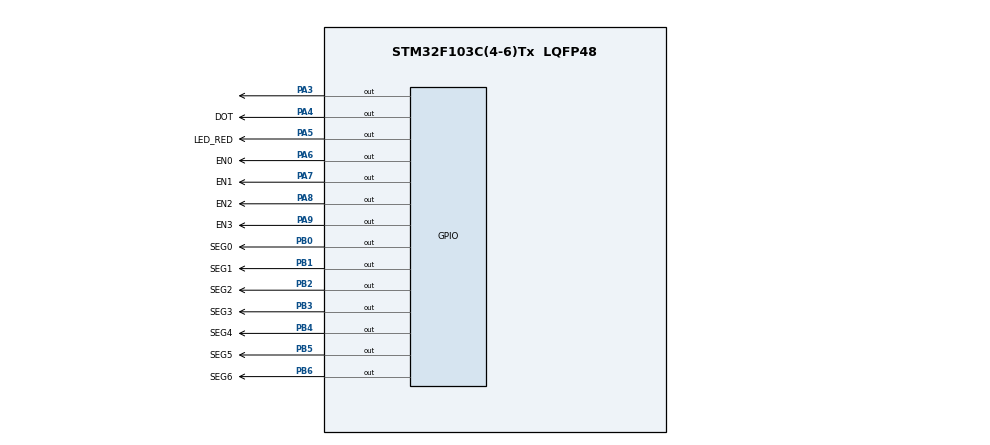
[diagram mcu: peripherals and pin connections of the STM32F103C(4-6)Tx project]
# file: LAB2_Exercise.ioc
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Mcu.Family=STM32F1
Mcu.Name=STM32F103C(4-6)Tx
Mcu.Package=LQFP48
NVIC.PriorityGroup=NVIC_PRIORITYGROUP_4
NVIC.TIM2_IRQn=true\:0\:0\:false\:false\:true\:true\:true
PA3.Signal=GPIO_Output
PA4.GPIO_Label=DOT
PA4.Signal=GPIO_Output
PA5.GPIO_Label=LED_RED
PA5.Signal=GPIO_Output
PA6.GPIO_Label=EN0
PA6.Signal=GPIO_Output
PA7.GPIO_Label=EN1
PA7.Signal=GPIO_Output
PA8.GPIO_Label=EN2
PA8.Signal=GPIO_Output
PA9.GPIO_Label=EN3
PA9.Signal=GPIO_Output
PB0.GPIO_Label=SEG0
PB0.Signal=GPIO_Output
PB1.GPIO_Label=SEG1
PB1.Signal=GPIO_Output
PB2.GPIO_Label=SEG2
PB2.Signal=GPIO_Output
PB3.GPIO_Label=SEG3
PB3.Signal=GPIO_Output
PB4.GPIO_Label=SEG4
PB4.Signal=GPIO_Output
PB5.GPIO_Label=SEG5
PB5.Signal=GPIO_Output
PB6.GPIO_Label=SEG6
PB6.Signal=GPIO_Output
ProjectManager.HeapSize=0x200
ProjectManager.StackSize=0x400
ProjectManager.TargetToolchain=STM32CubeIDE
RCC.APB1Freq_Value=8000000
RCC.APB2Freq_Value=8000000
TIM2.Period=9
TIM2.Prescaler=7999
VP_SYS_VS_ND.Mode=No_Debug
VP_TIM2_VS_ClockSourceINT.Mode=Internal
board=custom

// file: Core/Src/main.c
/* USER CODE BEGIN Header */
/**
  ******************************************************************************
  * @file           : main.c
  * @brief          : Main program body
  ******************************************************************************
  * @attention
  *
  * <h2><center>&copy; Copyright (c) 2023 STMicroelectronics.
  * All rights reserved.</center></h2>
  *
  * This software component is licensed by ST under BSD 3-Clause license,
  * the "License"; You may not use this file except in compliance with the
  * License. You may obtain a copy of the License at:
  *                        opensource.org/licenses/BSD-3-Clause
  *
  ******************************************************************************
  */
/* USER CODE END Header */
#include "main.h"

TIM_HandleTypeDef htim2;

/* USER CODE BEGIN PV */
int digit1 = 1;
int digit2 = 0;
int digit3 = 2;
int digit4 = 0;
int led_buffer[4] ;

void SystemClock_Config(void);
static void MX_GPIO_Init(void);
static void MX_TIM2_Init(void);
int timer1_flag = 0;
int counter1 = 0;
int timer2_flag = 0;
int counter2 = 0;
int timer3_flag = 0;
int counter3 = 0;
int timer0_flag = 0;
int counter0 =0;
int counter5 = 0;
int timer5_flag = 0;

void setTimer1(int duration){
	counter1 = duration;
	timer1_flag = 0;
}
void setTimer2(int duration){
	counter2 = duration;
	timer2_flag = 0;
}
void setTimer3(int duration){
	counter3 = duration;
	timer3_flag = 0;
}
void setTimer0(int duration){
	counter0 = duration;
	timer0_flag = 0;
}
void setTimer5( int duration ){
	counter5 = duration;
	timer5_flag = 0;
}
void timerRun(){
	if(counter1 > 0){
		counter1--;
		if(counter1 <= 0){
			timer1_flag = 1;
              }
	}
	 if(counter2 > 0){
			counter2 -- ;
				if(counter2 <= 0){
					timer2_flag = 1;
				}
			}
		if(counter3 > 0){
				counter3--;
				if(counter3 <= 0){
					timer3_flag = 1;
				}
			}
		if(counter0 > 0){
			counter0--;
			if (counter0 <= 0){
				timer0_flag = 1 ;
			}
		}
		if(counter5 > 0){
			counter5--;
			if (counter5 <= 0){
				timer5_flag = 1;
			}
		}
}

void HAL_TIM_PeriodElapsedCallback (TIM_HandleTypeDef *htim2 )
{
     timerRun();

}

void updateClockBuffer(int a, int b){
	digit1 = a/10;
	digit2 = a%10;
	digit3 = b/10;
	digit4 = b%10;
	led_buffer[0] = digit1;
	led_buffer[1] = digit2;
	led_buffer[2] = digit3;
	led_buffer[3] = digit4;
}

void SCAN(int n){
	switch (led_buffer[n]){
	   case 0:
	  		HAL_GPIO_WritePin(SEG0_GPIO_Port, SEG0_Pin, 0 );
	  		HAL_GPIO_WritePin(SEG1_GPIO_Port, SEG1_Pin, 0);
	  		HAL_GPIO_WritePin(SEG2_GPIO_Port, SEG2_Pin, 0);
	  		HAL_GPIO_WritePin(SEG3_GPIO_Port, SEG3_Pin,0 );
	  		HAL_GPIO_WritePin(SEG4_GPIO_Port, SEG4_Pin,0 );
	  		HAL_GPIO_WritePin(SEG5_GPIO_Port, SEG5_Pin, 0);
	  		HAL_GPIO_WritePin(SEG6_GPIO_Port, SEG6_Pin, 1);
	  		break;

	   case 1:
	 		HAL_GPIO_WritePin(SEG0_GPIO_Port, SEG0_Pin, 1);
	 		HAL_GPIO_WritePin(SEG1_GPIO_Port, SEG1_Pin, 0);
	 		HAL_GPIO_WritePin(SEG2_GPIO_Port, SEG2_Pin, 0);
	 		HAL_GPIO_WritePin(SEG3_GPIO_Port, SEG3_Pin, 1);
	 		HAL_GPIO_WritePin(SEG4_GPIO_Port, SEG4_Pin, 1);
	 		HAL_GPIO_WritePin(SEG5_GPIO_Port, SEG5_Pin, 1);
	 		HAL_GPIO_WritePin(SEG6_GPIO_Port, SEG6_Pin, 1);
	 		break;
	   case 2:
	 		HAL_GPIO_WritePin(SEG0_GPIO_Port, SEG0_Pin, 0);
	 		HAL_GPIO_WritePin(SEG1_GPIO_Port, SEG1_Pin, 0);
	 		HAL_GPIO_WritePin(SEG2_GPIO_Port, SEG2_Pin, 1);
	 		HAL_GPIO_WritePin(SEG3_GPIO_Port, SEG3_Pin, 0);
	 		HAL_GPIO_WritePin(SEG4_GPIO_Port, SEG4_Pin, 0);
	 		HAL_GPIO_WritePin(SEG5_GPIO_Port, SEG5_Pin, 1);
	 		HAL_GPIO_WritePin(SEG6_GPIO_Port, SEG6_Pin, 0);
	 		break;
	   case 3:
			HAL_GPIO_WritePin(SEG0_GPIO_Port, SEG0_Pin, 0);
			HAL_GPIO_WritePin(SEG1_GPIO_Port, SEG1_Pin, 0);
			HAL_GPIO_WritePin(SEG2_GPIO_Port, SEG2_Pin, 0);
			HAL_GPIO_WritePin(SEG3_GPIO_Port, SEG3_Pin, 0);
			HAL_GPIO_WritePin(SEG4_GPIO_Port, SEG4_Pin, 1);
			HAL_GPIO_WritePin(SEG5_GPIO_Port, SEG5_Pin, 1);
			HAL_GPIO_WritePin(SEG6_GPIO_Port, SEG6_Pin, 0);
			break;
	   case 4:
			HAL_GPIO_WritePin(SEG0_GPIO_Port, SEG0_Pin, 1 );
			HAL_GPIO_WritePin(SEG1_GPIO_Port, SEG1_Pin, 0 );
			HAL_GPIO_WritePin(SEG2_GPIO_Port, SEG2_Pin, 0);
			HAL_GPIO_WritePin(SEG3_GPIO_Port, SEG3_Pin, 1 );
			HAL_GPIO_WritePin(SEG4_GPIO_Port, SEG4_Pin, 1);
			HAL_GPIO_WritePin(SEG5_GPIO_Port, SEG5_Pin, 0);
			HAL_GPIO_WritePin(SEG6_GPIO_Port, SEG6_Pin, 0);
			break;
	   case 5:
			HAL_GPIO_WritePin(SEG0_GPIO_Port, SEG0_Pin, 0 );
			HAL_GPIO_WritePin(SEG1_GPIO_Port, SEG1_Pin, 1 );
			HAL_GPIO_WritePin(SEG2_GPIO_Port, SEG2_Pin, 0);
			HAL_GPIO_WritePin(SEG3_GPIO_Port, SEG3_Pin, 0 );
			HAL_GPIO_WritePin(SEG4_GPIO_Port, SEG4_Pin, 1 );
			HAL_GPIO_WritePin(SEG5_GPIO_Port, SEG5_Pin, 0);
			HAL_GPIO_WritePin(SEG6_GPIO_Port, SEG6_Pin, 0);
			break;
	   case 6:

			HAL_GPIO_WritePin(SEG0_GPIO_Port, SEG0_Pin, 0 );
			HAL_GPIO_WritePin(SEG1_GPIO_Port, SEG1_Pin, 1 );
			HAL_GPIO_WritePin(SEG2_GPIO_Port, SEG2_Pin, 0);
			HAL_GPIO_WritePin(SEG3_GPIO_Port, SEG3_Pin,0 );
			HAL_GPIO_WritePin(SEG4_GPIO_Port, SEG4_Pin,0 );
			HAL_GPIO_WritePin(SEG5_GPIO_Port, SEG5_Pin, 0);
			HAL_GPIO_WritePin(SEG6_GPIO_Port, SEG6_Pin, 0);
			break;
	   case 7:
			HAL_GPIO_WritePin(SEG0_GPIO_Port, SEG0_Pin, 0 );
			HAL_GPIO_WritePin(SEG1_GPIO_Port, SEG1_Pin, 0 );
			HAL_GPIO_WritePin(SEG2_GPIO_Port, SEG2_Pin, 0);
			HAL_GPIO_WritePin(SEG3_GPIO_Port, SEG3_Pin, 1 );
			HAL_GPIO_WritePin(SEG4_GPIO_Port, SEG4_Pin, 1 );
			HAL_GPIO_WritePin(SEG5_GPIO_Port, SEG5_Pin, 1);
			HAL_GPIO_WritePin(SEG6_GPIO_Port, SEG6_Pin, 1);
			break;
	   case 8:
			HAL_GPIO_WritePin(SEG0_GPIO_Port, SEG0_Pin, 0 );
			HAL_GPIO_WritePin(SEG1_GPIO_Port, SEG1_Pin, 0 );
			HAL_GPIO_WritePin(SEG2_GPIO_Port, SEG2_Pin, 0);
			HAL_GPIO_WritePin(SEG3_GPIO_Port, SEG3_Pin,0 );
			HAL_GPIO_WritePin(SEG4_GPIO_Port, SEG4_Pin,0 );
			HAL_GPIO_WritePin(SEG5_GPIO_Port, SEG5_Pin, 0);
			HAL_GPIO_WritePin(SEG6_GPIO_Port, SEG6_Pin, 0);
			break;
	   case 9:
			HAL_GPIO_WritePin(SEG0_GPIO_Port, SEG0_Pin, 0 );
			HAL_GPIO_WritePin(SEG1_GPIO_Port, SEG1_Pin, 0 );
			HAL_GPIO_WritePin(SEG2_GPIO_Port, SEG2_Pin, 0);
			HAL_GPIO_WritePin(SEG3_GPIO_Port, SEG3_Pin,0 );
			HAL_GPIO_WritePin(SEG4_GPIO_Port, SEG4_Pin, 1);
			HAL_GPIO_WritePin(SEG5_GPIO_Port, SEG5_Pin, 0);
			HAL_GPIO_WritePin(SEG6_GPIO_Port, SEG6_Pin, 0);
			break;
	   default:
		   break;
	}
}

void update7SEG(int index_led){
	switch (index_led){
	case 0:
		   HAL_GPIO_WritePin(EN0_GPIO_Port, EN0_Pin, 0);
		   HAL_GPIO_WritePin(EN1_GPIO_Port, EN1_Pin, 1);
		   HAL_GPIO_WritePin(EN2_GPIO_Port, EN2_Pin, 1);
		   HAL_GPIO_WritePin(EN3_GPIO_Port, EN3_Pin, 1);
		   SCAN(index_led);
		   break;
	case 1:
		   HAL_GPIO_WritePin(EN0_GPIO_Port, EN0_Pin, 1);
		   HAL_GPIO_WritePin(EN1_GPIO_Port, EN1_Pin, 0);
		   HAL_GPIO_WritePin(EN2_GPIO_Port, EN2_Pin, 1);
		   HAL_GPIO_WritePin(EN3_GPIO_Port, EN3_Pin, 1);
		   SCAN(index_led);
		   break;
	case 2:
		   HAL_GPIO_WritePin(EN0_GPIO_Port, EN0_Pin, 1);
		   HAL_GPIO_WritePin(EN1_GPIO_Port, EN1_Pin, 1);
		   HAL_GPIO_WritePin(EN2_GPIO_Port, EN2_Pin, 0);
		   HAL_GPIO_WritePin(EN3_GPIO_Port, EN3_Pin, 1);
		   SCAN(index_led);
		   break;
	case 3:
		   HAL_GPIO_WritePin(EN0_GPIO_Port, EN0_Pin, 1);
		   HAL_GPIO_WritePin(EN1_GPIO_Port, EN1_Pin, 1);
		   HAL_GPIO_WritePin(EN2_GPIO_Port, EN2_Pin, 1);
		   HAL_GPIO_WritePin(EN3_GPIO_Port, EN3_Pin, 0 );
		   SCAN(index_led);
		   break;
	default:
		break;
	}
}
const int MAX_LED_MATRIX = 8;
int index_led_matrix = 0;
uint8_t matrix_buffer [8] = {
  0b11100111,
  0b11000011,
  0b10011001,
  0b10011001,
  0b10000001,
  0b10000001,
  0b10011001,
  0b10011001,
};

void SCAN_LED_MATRIX(int index){

	  HAL_GPIO_WritePin(ROW0_GPIO_Port, ROW0_Pin, 0);
	  HAL_GPIO_WritePin(ROW1_GPIO_Port, ROW1_Pin, 0);
	  HAL_GPIO_WritePin(ROW2_GPIO_Port, ROW2_Pin, 0);
	  HAL_GPIO_WritePin(ROW3_GPIO_Port, ROW3_Pin, 0);
	  HAL_GPIO_WritePin(ROW4_GPIO_Port, ROW4_Pin, 0);
	  HAL_GPIO_WritePin(ROW5_GPIO_Port, ROW5_Pin, 0);
	  HAL_GPIO_WritePin(ROW6_GPIO_Port, ROW6_Pin, 0);
	  HAL_GPIO_WritePin(ROW7_GPIO_Port, ROW7_Pin, 0);

	  uint8_t row_value = matrix_buffer[index] >> 1;
	  if(row_value & 0b00000001) HAL_GPIO_WritePin(ROW0_GPIO_Port, ROW0_Pin, 1);
	  if(row_value & 0b00000010) HAL_GPIO_WritePin(ROW1_GPIO_Port, ROW1_Pin, 1);
	  if(row_value & 0b00000100) HAL_GPIO_WritePin(ROW2_GPIO_Port, ROW2_Pin, 1);
	  if(row_value & 0b00001000) HAL_GPIO_WritePin(ROW3_GPIO_Port, ROW3_Pin, 1);
	  if(row_value & 0b00010000) HAL_GPIO_WritePin(ROW4_GPIO_Port, ROW4_Pin, 1);
	  if(row_value & 0b00100000) HAL_GPIO_WritePin(ROW5_GPIO_Port, ROW5_Pin, 1);
	  if(row_value & 0b01000000) HAL_GPIO_WritePin(ROW6_GPIO_Port, ROW6_Pin, 1);
	  if(row_value & 0b10000000) HAL_GPIO_WritePin(ROW7_GPIO_Port, ROW7_Pin, 1);
}
uint8_t matrix_buffer_col [8] = {
		 0b00000001
		,0b00000010
		,0b00000100
		,0b00001000
		,0b00010000
		,0b00100000
		,0b01000000
		,0b10000000
};
void SCAN_LED_MATRIX_COL(int index){
	  HAL_GPIO_WritePin(ENM0_GPIO_Port, ENM0_Pin, 1);
	  HAL_GPIO_WritePin(ENM1_GPIO_Port, ENM1_Pin, 1);
	  HAL_GPIO_WritePin(ENM2_GPIO_Port, ENM2_Pin, 1);
	  HAL_GPIO_WritePin(ENM3_GPIO_Port, ENM3_Pin, 1);
	  HAL_GPIO_WritePin(ENM4_GPIO_Port, ENM4_Pin, 1);
	  HAL_GPIO_WritePin(ENM5_GPIO_Port, ENM5_Pin, 1);
	  HAL_GPIO_WritePin(ENM6_GPIO_Port, ENM6_Pin, 1);
	  HAL_GPIO_WritePin(ENM7_GPIO_Port, ENM7_Pin, 1);

	  uint8_t col_value = matrix_buffer_col[index];
	  if(col_value & 0b00000001)  HAL_GPIO_WritePin(ENM0_GPIO_Port, ENM0_Pin, 0);
	  if(col_value & 0b00000010)  HAL_GPIO_WritePin(ENM1_GPIO_Port, ENM1_Pin, 0);
	  if(col_value & 0b00000100)  HAL_GPIO_WritePin(ENM2_GPIO_Port, ENM2_Pin, 0);
	  if(col_value & 0b00001000)  HAL_GPIO_WritePin(ENM3_GPIO_Port, ENM3_Pin, 0);
	  if(col_value & 0b00010000)  HAL_GPIO_WritePin(ENM4_GPIO_Port, ENM4_Pin, 0);
	  if(col_value & 0b00100000)  HAL_GPIO_WritePin(ENM5_GPIO_Port, ENM5_Pin, 0);
	  if(col_value & 0b01000000)  HAL_GPIO_WritePin(ENM6_GPIO_Port, ENM6_Pin, 0);
	  if(col_value & 0b10000000)  HAL_GPIO_WritePin(ENM7_GPIO_Port, ENM7_Pin, 0);
}
void updateLEDMatrix (int index ){
switch ( index ) {
   case 0:
       SCAN_LED_MATRIX_COL(index);
       SCAN_LED_MATRIX(index);
       break ;
   case 1:
   	SCAN_LED_MATRIX_COL(index);
   	SCAN_LED_MATRIX(index);
       break ;
   case 2:
   	SCAN_LED_MATRIX_COL(index);
       SCAN_LED_MATRIX(index);
       break ;
   case 3:
   	SCAN_LED_MATRIX_COL(index);
   	SCAN_LED_MATRIX(index);
       break ;
   case 4:
   	SCAN_LED_MATRIX_COL(index);
   	SCAN_LED_MATRIX(index);
       break ;
   case 5:
   	SCAN_LED_MATRIX_COL(index);
   	SCAN_LED_MATRIX(index);
       break ;
   case 6:
   	SCAN_LED_MATRIX_COL(index);
   	SCAN_LED_MATRIX(index);
       break ;
   case 7:
   	SCAN_LED_MATRIX_COL(index);
   	SCAN_LED_MATRIX(index);
       break ;
        default :
        break ;
     }
}

int main(void)
{

  HAL_Init();
  SystemClock_Config();

  MX_GPIO_Init();
  MX_TIM2_Init();
  HAL_TIM_Base_Start_IT (& htim2 );

   int index_led=0;
   setTimer0(10);
   setTimer1(15);
   setTimer2(15);
   setTimer3(100);
   int MAX_LED_MATRIX = 8;
   int hour = 15 , minute = 8, second = 50;
  while (1)
  {
	  if(timer0_flag == 1){
	  second ++;
	  updateClockBuffer(hour, minute);
	  setTimer0(100);
	   if(second >= 60){
	  	minute++;
	  	second = 0;
	  	if(minute >= 60){
	  		minute = 0;
	  		hour++;}
	  		if(hour >= 24){
	  		hour = 0;
	  		}
	  	}
	  }
	  		  if(timer2_flag == 1){
	  		  	update7SEG(index_led);
	  		  	if(index_led >= 3){
	  		  		index_led = 0;
	  		  	}
	  		  	else{
	  		  		index_led++;
	  		  	}
	  		  	setTimer2(10);
	  		  }
	  		  if(timer1_flag == 1){
	  		  	HAL_GPIO_TogglePin(DOT_GPIO_Port, DOT_Pin);
	  		  	setTimer1(100);
	  		  }
	            if(timer3_flag == 1){
	          	  updateLEDMatrix(index_led_matrix++);
	          	  if(index_led_matrix == MAX_LED_MATRIX){
	          		 index_led_matrix = 0;
	          	  }
	          	  setTimer3(15);
	            }
  }

}

void SystemClock_Config(void)
{
  RCC_OscInitTypeDef RCC_OscInitStruct = {0};
  RCC_ClkInitTypeDef RCC_ClkInitStruct = {0};

  /** Initializes the RCC Oscillators according to the specified parameters
  * in the RCC_OscInitTypeDef structure.
  */
  RCC_OscInitStruct.OscillatorType = RCC_OSCILLATORTYPE_HSI;
  RCC_OscInitStruct.HSIState = RCC_HSI_ON;
  RCC_OscInitStruct.HSICalibrationValue = RCC_HSICALIBRATION_DEFAULT;
  RCC_OscInitStruct.PLL.PLLState = RCC_PLL_NONE;
  if (HAL_RCC_OscConfig(&RCC_OscInitStruct) != HAL_OK)
  {
    Error_Handler();
  }
  /** Initializes the CPU, AHB and APB buses clocks
  */
  RCC_ClkInitStruct.ClockType = RCC_CLOCKTYPE_HCLK|RCC_CLOCKTYPE_SYSCLK
                              |RCC_CLOCKTYPE_PCLK1|RCC_CLOCKTYPE_PCLK2;
  RCC_ClkInitStruct.SYSCLKSource = RCC_SYSCLKSOURCE_HSI;
  RCC_ClkInitStruct.AHBCLKDivider = RCC_SYSCLK_DIV1;
  RCC_ClkInitStruct.APB1CLKDivider = RCC_HCLK_DIV1;
  RCC_ClkInitStruct.APB2CLKDivider = RCC_HCLK_DIV1;

  if (HAL_RCC_ClockConfig(&RCC_ClkInitStruct, FLASH_LATENCY_0) != HAL_OK)
  {
    Error_Handler();
  }
}

static void MX_TIM2_Init(void)
{

  TIM_ClockConfigTypeDef sClockSourceConfig = {0};
  TIM_MasterConfigTypeDef sMasterConfig = {0};

  htim2.Instance = TIM2;
  htim2.Init.Prescaler = 7999;
  htim2.Init.CounterMode = TIM_COUNTERMODE_UP;
  htim2.Init.Period = 9;
  htim2.Init.ClockDivision = TIM_CLOCKDIVISION_DIV1;
  htim2.Init.AutoReloadPreload = TIM_AUTORELOAD_PRELOAD_DISABLE;
  if (HAL_TIM_Base_Init(&htim2) != HAL_OK)
  {
    Error_Handler();
  }
  sClockSourceConfig.ClockSource = TIM_CLOCKSOURCE_INTERNAL;
  if (HAL_TIM_ConfigClockSource(&htim2, &sClockSourceConfig) != HAL_OK)
  {
    Error_Handler();
  }
  sMasterConfig.MasterOutputTrigger = TIM_TRGO_RESET;
  sMasterConfig.MasterSlaveMode = TIM_MASTERSLAVEMODE_DISABLE;
  if (HAL_TIMEx_MasterConfigSynchronization(&htim2, &sMasterConfig) != HAL_OK)
  {
    Error_Handler();
  }

}

static void MX_GPIO_Init(void)
{
  GPIO_InitTypeDef GPIO_InitStruct = {0};

  /* GPIO Ports Clock Enable */
  __HAL_RCC_GPIOA_CLK_ENABLE();
  __HAL_RCC_GPIOB_CLK_ENABLE();

  /*Configure GPIO pin Output Level */
  HAL_GPIO_WritePin(GPIOA, ENM0_Pin|ENM1_Pin|DOT_Pin|LED_RED_Pin
                          |EN0_Pin|EN1_Pin|EN2_Pin|EN3_Pin
                          |ENM2_Pin|ENM3_Pin|ENM4_Pin|ENM5_Pin
                          |ENM6_Pin|ENM7_Pin, GPIO_PIN_RESET);

  /*Configure GPIO pin Output Level */
  HAL_GPIO_WritePin(GPIOB, SEG0_Pin|SEG1_Pin|SEG2_Pin|ROW2_Pin
                          |ROW3_Pin|ROW4_Pin|ROW5_Pin|ROW6_Pin
                          |ROW7_Pin|SEG3_Pin|SEG4_Pin|SEG5_Pin
                          |SEG6_Pin|ROW0_Pin|ROW1_Pin, GPIO_PIN_RESET);

  /*Configure GPIO pins : ENM0_Pin ENM1_Pin DOT_Pin LED_RED_Pin
                           EN0_Pin EN1_Pin EN2_Pin EN3_Pin
                           ENM2_Pin ENM3_Pin ENM4_Pin ENM5_Pin
                           ENM6_Pin ENM7_Pin */
  GPIO_InitStruct.Pin = ENM0_Pin|ENM1_Pin|DOT_Pin|LED_RED_Pin
                          |EN0_Pin|EN1_Pin|EN2_Pin|EN3_Pin
                          |ENM2_Pin|ENM3_Pin|ENM4_Pin|ENM5_Pin
                          |ENM6_Pin|ENM7_Pin;
  GPIO_InitStruct.Mode = GPIO_MODE_OUTPUT_PP;
  GPIO_InitStruct.Pull = GPIO_NOPULL;
  GPIO_InitStruct.Speed = GPIO_SPEED_FREQ_LOW;
  HAL_GPIO_Init(GPIOA, &GPIO_InitStruct);

  /*Configure GPIO pins : SEG0_Pin SEG1_Pin SEG2_Pin ROW2_Pin
                           ROW3_Pin ROW4_Pin ROW5_Pin ROW6_Pin
                           ROW7_Pin SEG3_Pin SEG4_Pin SEG5_Pin
                           SEG6_Pin ROW0_Pin ROW1_Pin */
  GPIO_InitStruct.Pin = SEG0_Pin|SEG1_Pin|SEG2_Pin|ROW2_Pin
                          |ROW3_Pin|ROW4_Pin|ROW5_Pin|ROW6_Pin
                          |ROW7_Pin|SEG3_Pin|SEG4_Pin|SEG5_Pin
                          |SEG6_Pin|ROW0_Pin|ROW1_Pin;
  GPIO_InitStruct.Mode = GPIO_MODE_OUTPUT_PP;
  GPIO_InitStruct.Pull = GPIO_NOPULL;
  GPIO_InitStruct.Speed = GPIO_SPEED_FREQ_LOW;
  HAL_GPIO_Init(GPIOB, &GPIO_InitStruct);

}

void Error_Handler(void)
{
  __disable_irq();
  while (1)
  {
  }
}

/************************ (C) COPYRIGHT STMicroelectronics *****END OF FILE****/
